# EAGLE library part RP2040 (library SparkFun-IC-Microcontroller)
Raspberry Pi RP2040 MCU 56-pin 32-bit Microcontroller with 264kB of SRAM and external flash support up to 16MB Getting Started with the RP2040 Dual-core ARM Cortex M0+ processor, flexible clock running up to 133 MHz 264kB of SRAM, and QSPI control of common flash memory USB 1.1 Host and Device support Low-power sleep and dormant modes Drag & drop programming using mass storage over USB 26 multi-function GPIO pins 2×SPI, 2×I2C, 2×UART, 3×12-bit ADC, 16×controllable PWM channels Accurate clock and timer on-chip Temperature sensor Accelerated floating point libraries on-chip 8×Programmable IO (PIO) state machines for custom peripheral support

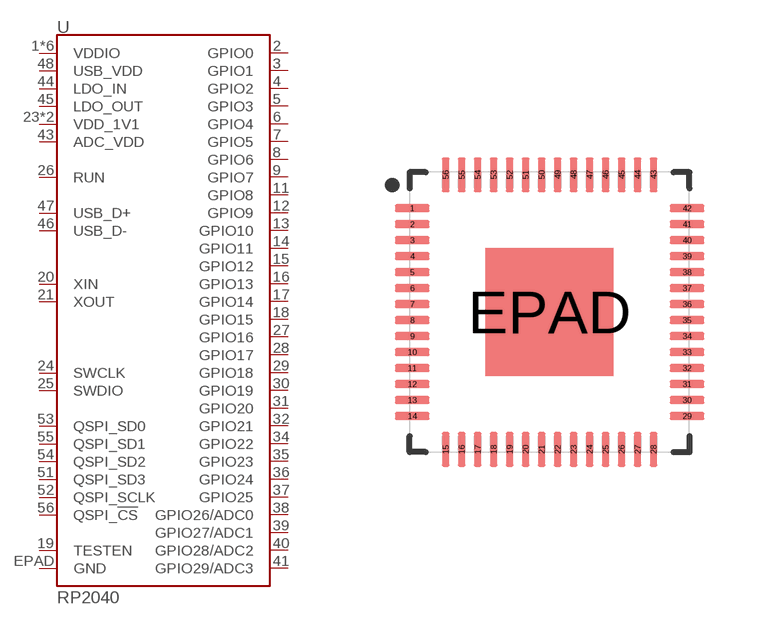
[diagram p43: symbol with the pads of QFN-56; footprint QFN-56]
Designator prefix U

## RP2040 (PROD_ID: IC-15502)  [QFN-56]
1  VDDIO
2  GPIO0
3  GPIO1
4  GPIO2
5  GPIO3
6  GPIO4
7  GPIO5
8  GPIO6
9  GPIO7
10  VDDIO
11  GPIO8
12  GPIO9
13  GPIO10
14  GPIO11
15  GPIO12
16  GPIO13
17  GPIO14
18  GPIO15
19  TESTEN
20  XIN
21  XOUT
22  VDDIO
23  VDD_1V1
24  SWCLK
25  SWDIO
26  RUN
27  GPIO16
28  GPIO17
29  GPIO18
30  GPIO19
31  GPIO20
32  GPIO21
33  VDDIO
34  GPIO22
35  GPIO23
36  GPIO24
37  GPIO25
38  GPIO26/ADC0
39  GPIO27/ADC1
40  GPIO28/ADC2
41  GPIO29/ADC3
42  VDDIO
43  ADC_VDD
44  LDO_IN
45  LDO_OUT
46  USB_D-
47  USB_D+
48  USB_VDD
49  VDDIO
50  VDD_1V1
51  QSPI_SD3
52  QSPI_SCLK
53  QSPI_SD0
54  QSPI_SD2
55  QSPI_SD1
56  QSPI_!CS!
EPAD  GND

## Footprint QFN-56 (pad centres in mm)
smd 0.875 x 0.2: 1 -3.437,2.6; 2 -3.437,2.2; 3 -3.437,1.8; 4 -3.437,1.4; 5 -3.437,1; 6 -3.437,0.6; 7 -3.437,0.2; 8 -3.437,-0.2; 9 -3.437,-0.6; 10 -3.437,-1; 11 -3.437,-1.4; 12 -3.437,-1.8; 13 -3.437,-2.2; 14 -3.437,-2.6; 29 3.437,-2.6; 30 3.437,-2.2; 31 3.437,-1.8; 32 3.437,-1.4; 33 3.437,-1; 34 3.437,-0.6; 35 3.437,-0.2; 36 3.437,0.2; 37 3.437,0.6; 38 3.437,1; 39 3.437,1.4; 40 3.437,1.8; 41 3.437,2.2; 42 3.437,2.6
smd 0.2 x 0.875: 15 -2.6,-3.437; 16 -2.2,-3.437; 17 -1.8,-3.437; 18 -1.4,-3.437; 19 -1,-3.437; 20 -0.6,-3.437; 21 -0.2,-3.437; 22 0.2,-3.437; 23 0.6,-3.437; 24 1,-3.437; 25 1.4,-3.437; 26 1.8,-3.437; 27 2.2,-3.437; 28 2.6,-3.437; 43 2.6,3.437; 44 2.2,3.437; 45 1.8,3.437; 46 1.4,3.437; 47 1,3.437; 48 0.6,3.437; 49 0.2,3.437; 50 -0.2,3.437; 51 -0.6,3.437; 52 -1,3.437; 53 -1.4,3.437; 54 -1.8,3.437; 55 -2.2,3.437; 56 -2.6,3.437
smd 3.2 x 3.2: EPAD 0,0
